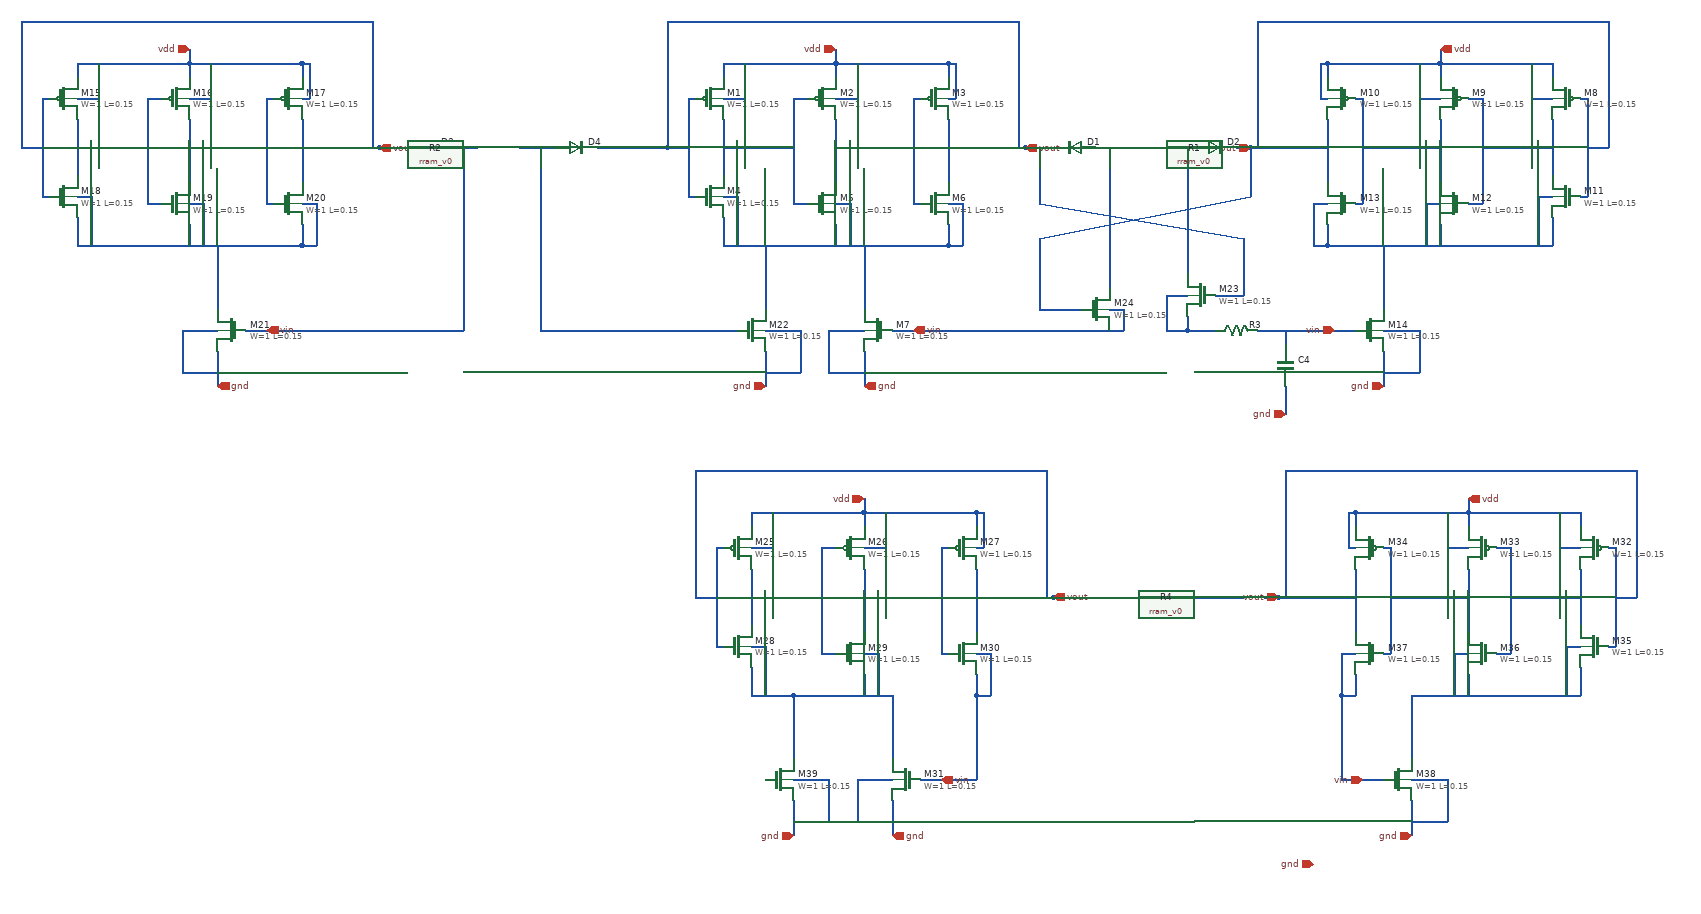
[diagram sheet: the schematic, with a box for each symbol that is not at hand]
v {xschem version=3.4.5 file_version=1.2
}
G {}
K {}
V {}
S {}
E {}
N 170 -200 170 -120 {
lab=#net1}
N 330 -200 330 -110 {
lab=#net2}
N 490 -200 490 -110 {
lab=vout}
N 270 -230 290 -230 {
lab=#net1}
N 270 -230 270 -80 {
lab=#net1}
N 270 -80 290 -80 {
lab=#net1}
N 440 -80 450 -80 {
lab=#net2}
N 440 -230 440 -80 {
lab=#net2}
N 440 -230 450 -230 {
lab=#net2}
N 120 -90 130 -90 {
lab=vout}
N 120 -230 120 -90 {
lab=vout}
N 120 -230 130 -230 {
lab=vout}
N 170 -280 170 -260 {
lab=vdd}
N 170 -280 330 -280 {
lab=vdd}
N 330 -300 330 -280 {
lab=vdd}
N 330 -280 490 -280 {
lab=vdd}
N 490 -280 490 -260 {
lab=vdd}
N 330 -280 330 -260 {
lab=vdd}
N 170 -160 270 -160 {
lab=#net1}
N 330 -160 440 -160 {
lab=#net2}
N 490 -160 520 -160 {
lab=vout}
N 520 -160 600 -160 {
lab=vout}
N 590 -160 600 -160 {
lab=vout}
N 590 -340 590 -160 {
lab=vout}
N 90 -340 590 -340 {
lab=vout}
N 90 -340 90 -160 {
lab=vout}
N 90 -160 120 -160 {
lab=vout}
N 170 -60 170 -20 {
lab=#net3}
N 170 -20 490 -20 {
lab=#net3}
N 490 -50 490 -20 {
lab=#net3}
N 330 -50 330 -20 {
lab=#net3}
N 370 -20 370 70 {
lab=#net3}
N 370 130 370 180 {
lab=gnd}
N 320 100 370 100 {
lab=gnd}
N 320 100 320 160 {
lab=gnd}
N 320 160 370 160 {
lab=gnd}
N 330 -80 350 -80 {
lab=#net3}
N 350 -80 350 -20 {
lab=#net3}
N 490 -80 510 -80 {
lab=#net3}
N 510 -80 510 -20 {
lab=#net3}
N 490 -20 510 -20 {
lab=#net3}
N 170 -90 190 -90 {
lab=#net3}
N 190 -90 190 -20 {
lab=#net3}
N 200 -280 200 -230 {
lab=vdd}
N 170 -230 200 -230 {
lab=vdd}
N 330 -230 360 -230 {
lab=vdd}
N 360 -280 360 -230 {
lab=vdd}
N 490 -230 500 -230 {
lab=vdd}
N 500 -280 500 -230 {
lab=vdd}
N 490 -280 500 -280 {
lab=vdd}
N 410 100 440 100 {
lab=vin}
N 1350 -200 1350 -120 {
lab=#net4}
N 1190 -200 1190 -110 {
lab=#net5}
N 1030 -200 1030 -110 {
lab=vout}
N 1230 -230 1250 -230 {
lab=#net4}
N 1250 -230 1250 -80 {
lab=#net4}
N 1230 -80 1250 -80 {
lab=#net4}
N 1070 -80 1080 -80 {
lab=#net5}
N 1080 -230 1080 -80 {
lab=#net5}
N 1070 -230 1080 -230 {
lab=#net5}
N 1390 -90 1400 -90 {
lab=vout}
N 1400 -230 1400 -90 {
lab=vout}
N 1390 -230 1400 -230 {
lab=vout}
N 1350 -280 1350 -260 {
lab=vdd}
N 1190 -280 1350 -280 {
lab=vdd}
N 1190 -300 1190 -280 {
lab=vdd}
N 1030 -280 1190 -280 {
lab=vdd}
N 1030 -280 1030 -260 {
lab=vdd}
N 1190 -280 1190 -260 {
lab=vdd}
N 1250 -160 1350 -160 {
lab=#net4}
N 1080 -160 1190 -160 {
lab=#net5}
N 1000 -160 1030 -160 {
lab=vout}
N 920 -160 1000 -160 {
lab=vout}
N 920 -160 930 -160 {
lab=vout}
N 930 -340 930 -160 {
lab=vout}
N 930 -340 1430 -340 {
lab=vout}
N 1430 -340 1430 -160 {
lab=vout}
N 1400 -160 1430 -160 {
lab=vout}
N 1350 -60 1350 -20 {
lab=#net6}
N 1030 -20 1350 -20 {
lab=#net6}
N 1030 -50 1030 -20 {
lab=#net6}
N 1190 -50 1190 -20 {
lab=#net6}
N 1110 -20 1110 70 {
lab=#net6}
N 1110 130 1110 180 {
lab=gnd}
N 1110 100 1160 100 {
lab=gnd}
N 1160 100 1160 160 {
lab=gnd}
N 1110 160 1160 160 {
lab=gnd}
N 1170 -80 1190 -80 {
lab=#net6}
N 1170 -80 1170 -20 {
lab=#net6}
N 1010 -80 1030 -80 {
lab=#net6}
N 1010 -80 1010 -20 {
lab=#net6}
N 1010 -20 1030 -20 {
lab=#net6}
N 1330 -90 1350 -90 {
lab=#net6}
N 1330 -90 1330 -20 {
lab=#net6}
N 1320 -280 1320 -230 {
lab=vdd}
N 1320 -230 1350 -230 {
lab=vdd}
N 1160 -230 1190 -230 {
lab=vdd}
N 1160 -280 1160 -230 {
lab=vdd}
N 1020 -230 1030 -230 {
lab=vdd}
N 1020 -280 1020 -230 {
lab=vdd}
N 1020 -280 1030 -280 {
lab=vdd}
N 1040 100 1070 100 {
lab=vin}
N 600 -160 640 -160 {
lab=vout}
N 700 -160 740 -160 {
lab=#net7}
N 900 -160 920 -160 {
lab=vout}
N 800 -160 840 -160 {
lab=#net8}
N 440 100 720 100 {
lab=vin}
N -750 -200 -750 -120 {
lab=#net9}
N -590 -200 -590 -110 {
lab=#net10}
N -430 -200 -430 -110 {
lab=vout}
N -650 -230 -630 -230 {
lab=#net9}
N -650 -230 -650 -80 {
lab=#net9}
N -650 -80 -630 -80 {
lab=#net9}
N -480 -80 -470 -80 {
lab=#net10}
N -480 -230 -480 -80 {
lab=#net10}
N -480 -230 -470 -230 {
lab=#net10}
N -800 -90 -790 -90 {
lab=vout}
N -800 -230 -800 -90 {
lab=vout}
N -800 -230 -790 -230 {
lab=vout}
N -750 -280 -750 -260 {
lab=vdd}
N -750 -280 -590 -280 {
lab=vdd}
N -590 -300 -590 -280 {
lab=vdd}
N -590 -280 -430 -280 {
lab=vdd}
N -430 -280 -430 -260 {
lab=vdd}
N -590 -280 -590 -260 {
lab=vdd}
N -750 -160 -650 -160 {
lab=#net9}
N -590 -160 -480 -160 {
lab=#net10}
N -430 -160 -400 -160 {
lab=vout}
N -400 -160 -320 -160 {
lab=vout}
N -330 -160 -320 -160 {
lab=vout}
N -330 -340 -330 -160 {
lab=vout}
N -830 -340 -330 -340 {
lab=vout}
N -830 -340 -830 -160 {
lab=vout}
N -830 -160 -800 -160 {
lab=vout}
N -750 -60 -750 -20 {
lab=#net11}
N -750 -20 -430 -20 {
lab=#net11}
N -430 -50 -430 -20 {
lab=#net11}
N -590 -50 -590 -20 {
lab=#net11}
N -550 -20 -550 70 {
lab=#net11}
N -550 130 -550 180 {
lab=gnd}
N -600 100 -550 100 {
lab=gnd}
N -600 100 -600 160 {
lab=gnd}
N -600 160 -550 160 {
lab=gnd}
N -590 -80 -570 -80 {
lab=#net11}
N -570 -80 -570 -20 {
lab=#net11}
N -430 -80 -410 -80 {
lab=#net11}
N -410 -80 -410 -20 {
lab=#net11}
N -430 -20 -410 -20 {
lab=#net11}
N -750 -90 -730 -90 {
lab=#net11}
N -730 -90 -730 -20 {
lab=#net11}
N -720 -280 -720 -230 {
lab=vdd}
N -750 -230 -720 -230 {
lab=vdd}
N -590 -230 -560 -230 {
lab=vdd}
N -560 -280 -560 -230 {
lab=vdd}
N -430 -230 -420 -230 {
lab=vdd}
N -420 -280 -420 -230 {
lab=vdd}
N -430 -280 -420 -280 {
lab=vdd}
N -510 100 -480 100 {
lab=vin}
N -320 -160 -280 -160 {
lab=vout}
N -220 -160 -180 -160 {
lab=vin}
N -200 -160 -200 100 {
lab=vin}
N -480 100 -200 100 {
lab=vin}
N -120 -160 -70 -160 {
lab=#net12}
N -10 -160 90 -160 {
lab=vout}
N -90 -160 -90 100 {
lab=#net12}
N 230 -20 230 70 {
lab=#net3}
N 230 130 230 180 {
lab=gnd}
N 230 100 280 100 {
lab=gnd}
N 280 100 280 160 {
lab=gnd}
N 230 160 280 160 {
lab=gnd}
N -90 100 190 100 {
lab=#net12}
N 830 100 870 100 {
lab=#net13}
N 970 100 970 120 {
lab=vin}
N 930 100 970 100 {
lab=vin}
N 930 100 1040 100 {
lab=vin}
N 970 180 970 220 {
lab=gnd}
N 830 80 830 100 {
lab=#net13}
N 830 -160 830 20 {
lab=#net8}
N 800 50 830 50 {
lab=#net13}
N 800 50 800 100 {
lab=#net13}
N 800 100 830 100 {
lab=#net13}
N 870 50 890 50 {
lab=vout}
N 720 70 740 70 {
lab=vin}
N 740 70 740 100 {
lab=vin}
N 720 100 740 100 {
lab=vin}
N 720 -160 720 40 {
lab=#net7}
N 650 70 680 70 {
lab=vout}
N 620 -160 620 -80 {
lab=vout}
N 620 -80 910 -30 {
lab=vout}
N 910 -30 910 50 {
lab=vout}
N 890 50 910 50 {
lab=vout}
N 920 -160 920 -90 {
lab=vout}
N 620 -30 920 -90 {
lab=vout}
N 620 -30 620 70 {
lab=vout}
N 620 70 650 70 {
lab=vout}
N 210 440 210 520 {
lab=#net14}
N 370 440 370 530 {
lab=#net15}
N 530 440 530 530 {
lab=vout}
N 310 410 330 410 {
lab=#net14}
N 310 410 310 560 {
lab=#net14}
N 310 560 330 560 {
lab=#net14}
N 480 560 490 560 {
lab=#net15}
N 480 410 480 560 {
lab=#net15}
N 480 410 490 410 {
lab=#net15}
N 160 550 170 550 {
lab=vout}
N 160 410 160 550 {
lab=vout}
N 160 410 170 410 {
lab=vout}
N 210 360 210 380 {
lab=vdd}
N 210 360 370 360 {
lab=vdd}
N 370 340 370 360 {
lab=vdd}
N 370 360 530 360 {
lab=vdd}
N 530 360 530 380 {
lab=vdd}
N 370 360 370 380 {
lab=vdd}
N 210 480 310 480 {
lab=#net14}
N 370 480 480 480 {
lab=#net15}
N 530 480 560 480 {
lab=vout}
N 560 480 640 480 {
lab=vout}
N 630 480 640 480 {
lab=vout}
N 630 300 630 480 {
lab=vout}
N 130 300 630 300 {
lab=vout}
N 130 300 130 480 {
lab=vout}
N 130 480 160 480 {
lab=vout}
N 210 580 210 620 {
lab=#net16}
N 530 590 530 620 {
lab=#net16}
N 370 590 370 620 {
lab=#net16}
N 410 620 410 710 {
lab=#net16}
N 410 770 410 820 {
lab=gnd}
N 360 740 410 740 {
lab=gnd}
N 360 740 360 800 {
lab=gnd}
N 360 800 410 800 {
lab=gnd}
N 370 560 390 560 {
lab=#net16}
N 390 560 390 620 {
lab=#net16}
N 530 560 550 560 {
lab=#net16}
N 550 560 550 620 {
lab=#net16}
N 530 620 550 620 {
lab=#net16}
N 210 550 230 550 {
lab=#net16}
N 230 550 230 620 {
lab=#net16}
N 240 360 240 410 {
lab=vdd}
N 210 410 240 410 {
lab=vdd}
N 370 410 400 410 {
lab=vdd}
N 400 360 400 410 {
lab=vdd}
N 530 410 540 410 {
lab=vdd}
N 540 360 540 410 {
lab=vdd}
N 530 360 540 360 {
lab=vdd}
N 450 740 480 740 {
lab=vin}
N 1390 440 1390 520 {
lab=#net17}
N 1230 440 1230 530 {
lab=#net18}
N 1070 440 1070 530 {
lab=vout}
N 1270 410 1290 410 {
lab=#net17}
N 1290 410 1290 560 {
lab=#net17}
N 1270 560 1290 560 {
lab=#net17}
N 1110 560 1120 560 {
lab=#net18}
N 1120 410 1120 560 {
lab=#net18}
N 1110 410 1120 410 {
lab=#net18}
N 1430 550 1440 550 {
lab=vout}
N 1440 410 1440 550 {
lab=vout}
N 1430 410 1440 410 {
lab=vout}
N 1390 360 1390 380 {
lab=vdd}
N 1230 360 1390 360 {
lab=vdd}
N 1230 340 1230 360 {
lab=vdd}
N 1070 360 1230 360 {
lab=vdd}
N 1070 360 1070 380 {
lab=vdd}
N 1230 360 1230 380 {
lab=vdd}
N 1290 480 1390 480 {
lab=#net17}
N 1120 480 1230 480 {
lab=#net18}
N 1040 480 1070 480 {
lab=vout}
N 960 480 1040 480 {
lab=vout}
N 960 480 970 480 {
lab=vout}
N 970 300 970 480 {
lab=vout}
N 970 300 1470 300 {
lab=vout}
N 1470 300 1470 480 {
lab=vout}
N 1440 480 1470 480 {
lab=vout}
N 1390 580 1390 620 {
lab=#net19}
N 1070 590 1070 620 {
lab=#net19}
N 1230 590 1230 620 {
lab=#net19}
N 1150 620 1150 710 {
lab=#net19}
N 1150 770 1150 820 {
lab=gnd}
N 1150 740 1200 740 {
lab=gnd}
N 1200 740 1200 800 {
lab=gnd}
N 1150 800 1200 800 {
lab=gnd}
N 1210 560 1230 560 {
lab=#net19}
N 1210 560 1210 620 {
lab=#net19}
N 1050 560 1070 560 {
lab=#net19}
N 1050 560 1050 620 {
lab=#net19}
N 1050 620 1070 620 {
lab=#net19}
N 1370 550 1390 550 {
lab=#net19}
N 1370 550 1370 620 {
lab=#net19}
N 1360 360 1360 410 {
lab=vdd}
N 1360 410 1390 410 {
lab=vdd}
N 1200 410 1230 410 {
lab=vdd}
N 1200 360 1200 410 {
lab=vdd}
N 1060 410 1070 410 {
lab=vdd}
N 1060 360 1060 410 {
lab=vdd}
N 1060 360 1070 360 {
lab=vdd}
N 1080 740 1110 740 {
lab=vin}
N 640 480 680 480 {
lab=vout}
N 740 480 780 480 {
lab=#net20}
N 940 480 960 480 {
lab=vout}
N 840 480 880 480 {
lab=#net21}
N 270 620 270 710 {
lab=#net16}
N 270 770 270 820 {
lab=gnd}
N 270 740 320 740 {
lab=gnd}
N 320 740 320 800 {
lab=gnd}
N 270 800 320 800 {
lab=gnd}
N 680 480 740 480 {}
N 880 480 910 480 {}
N 270 620 410 620 {}
N 210 620 270 620 {}
N 530 620 530 740 {}
N 1150 620 1390 620 {}
N 1050 620 1050 740 {}
N 1050 740 1080 740 {}
N 480 740 530 740 {}
C {sky130_fd_pr/pfet_01v8.sym} 150 -230 0 0 {name=M1
L=0.15
W=1
nf=1
mult=1
ad="'int((nf+1)/2) * W/nf * 0.29'" 
pd="'2*int((nf+1)/2) * (W/nf + 0.29)'"
as="'int((nf+2)/2) * W/nf * 0.29'" 
ps="'2*int((nf+2)/2) * (W/nf + 0.29)'"
nrd="'0.29 / W'" nrs="'0.29 / W'"
sa=0 sb=0 sd=0
model=pfet_01v8
spiceprefix=X
}
C {sky130_fd_pr/pfet_01v8.sym} 310 -230 0 0 {name=M2
L=0.15
W=1
nf=1
mult=1
ad="'int((nf+1)/2) * W/nf * 0.29'" 
pd="'2*int((nf+1)/2) * (W/nf + 0.29)'"
as="'int((nf+2)/2) * W/nf * 0.29'" 
ps="'2*int((nf+2)/2) * (W/nf + 0.29)'"
nrd="'0.29 / W'" nrs="'0.29 / W'"
sa=0 sb=0 sd=0
model=pfet_01v8
spiceprefix=X
}
C {sky130_fd_pr/pfet_01v8.sym} 470 -230 0 0 {name=M3
L=0.15
W=1
nf=1
mult=1
ad="'int((nf+1)/2) * W/nf * 0.29'" 
pd="'2*int((nf+1)/2) * (W/nf + 0.29)'"
as="'int((nf+2)/2) * W/nf * 0.29'" 
ps="'2*int((nf+2)/2) * (W/nf + 0.29)'"
nrd="'0.29 / W'" nrs="'0.29 / W'"
sa=0 sb=0 sd=0
model=pfet_01v8
spiceprefix=X
}
C {sky130_fd_pr/nfet_01v8.sym} 150 -90 0 0 {name=M4
L=0.15
W=1
nf=1 
mult=1
ad="'int((nf+1)/2) * W/nf * 0.29'" 
pd="'2*int((nf+1)/2) * (W/nf + 0.29)'"
as="'int((nf+2)/2) * W/nf * 0.29'" 
ps="'2*int((nf+2)/2) * (W/nf + 0.29)'"
nrd="'0.29 / W'" nrs="'0.29 / W'"
sa=0 sb=0 sd=0
model=nfet_01v8
spiceprefix=X
}
C {sky130_fd_pr/nfet_01v8.sym} 310 -80 0 0 {name=M5
L=0.15
W=1
nf=1 
mult=1
ad="'int((nf+1)/2) * W/nf * 0.29'" 
pd="'2*int((nf+1)/2) * (W/nf + 0.29)'"
as="'int((nf+2)/2) * W/nf * 0.29'" 
ps="'2*int((nf+2)/2) * (W/nf + 0.29)'"
nrd="'0.29 / W'" nrs="'0.29 / W'"
sa=0 sb=0 sd=0
model=nfet_01v8
spiceprefix=X
}
C {sky130_fd_pr/nfet_01v8.sym} 470 -80 0 0 {name=M6
L=0.15
W=1
nf=1 
mult=1
ad="'int((nf+1)/2) * W/nf * 0.29'" 
pd="'2*int((nf+1)/2) * (W/nf + 0.29)'"
as="'int((nf+2)/2) * W/nf * 0.29'" 
ps="'2*int((nf+2)/2) * (W/nf + 0.29)'"
nrd="'0.29 / W'" nrs="'0.29 / W'"
sa=0 sb=0 sd=0
model=nfet_01v8
spiceprefix=X
}
C {sky130_fd_pr/nfet_01v8.sym} 390 100 0 1 {name=M7
L=0.15
W=1
nf=1 
mult=1
ad="'int((nf+1)/2) * W/nf * 0.29'" 
pd="'2*int((nf+1)/2) * (W/nf + 0.29)'"
as="'int((nf+2)/2) * W/nf * 0.29'" 
ps="'2*int((nf+2)/2) * (W/nf + 0.29)'"
nrd="'0.29 / W'" nrs="'0.29 / W'"
sa=0 sb=0 sd=0
model=nfet_01v8
spiceprefix=X
}
C {devices/iopin.sym} 370 180 3 1 {name=p1 lab=gnd}
C {devices/iopin.sym} 330 -300 2 0 {name=p2 lab=vdd}
C {devices/ipin.sym} 440 100 0 1 {name=p3 lab=vin}
C {devices/opin.sym} 600 -160 0 0 {name=p4 lab=vout}
C {sky130_fd_pr/pfet_01v8.sym} 1370 -230 0 1 {name=M8
L=0.15
W=1
nf=1
mult=1
ad="'int((nf+1)/2) * W/nf * 0.29'" 
pd="'2*int((nf+1)/2) * (W/nf + 0.29)'"
as="'int((nf+2)/2) * W/nf * 0.29'" 
ps="'2*int((nf+2)/2) * (W/nf + 0.29)'"
nrd="'0.29 / W'" nrs="'0.29 / W'"
sa=0 sb=0 sd=0
model=pfet_01v8
spiceprefix=X
}
C {sky130_fd_pr/pfet_01v8.sym} 1210 -230 0 1 {name=M9
L=0.15
W=1
nf=1
mult=1
ad="'int((nf+1)/2) * W/nf * 0.29'" 
pd="'2*int((nf+1)/2) * (W/nf + 0.29)'"
as="'int((nf+2)/2) * W/nf * 0.29'" 
ps="'2*int((nf+2)/2) * (W/nf + 0.29)'"
nrd="'0.29 / W'" nrs="'0.29 / W'"
sa=0 sb=0 sd=0
model=pfet_01v8
spiceprefix=X
}
C {sky130_fd_pr/pfet_01v8.sym} 1050 -230 0 1 {name=M10
L=0.15
W=1
nf=1
mult=1
ad="'int((nf+1)/2) * W/nf * 0.29'" 
pd="'2*int((nf+1)/2) * (W/nf + 0.29)'"
as="'int((nf+2)/2) * W/nf * 0.29'" 
ps="'2*int((nf+2)/2) * (W/nf + 0.29)'"
nrd="'0.29 / W'" nrs="'0.29 / W'"
sa=0 sb=0 sd=0
model=pfet_01v8
spiceprefix=X
}
C {sky130_fd_pr/nfet_01v8.sym} 1370 -90 0 1 {name=M11
L=0.15
W=1
nf=1 
mult=1
ad="'int((nf+1)/2) * W/nf * 0.29'" 
pd="'2*int((nf+1)/2) * (W/nf + 0.29)'"
as="'int((nf+2)/2) * W/nf * 0.29'" 
ps="'2*int((nf+2)/2) * (W/nf + 0.29)'"
nrd="'0.29 / W'" nrs="'0.29 / W'"
sa=0 sb=0 sd=0
model=nfet_01v8
spiceprefix=X
}
C {sky130_fd_pr/nfet_01v8.sym} 1210 -80 0 1 {name=M12
L=0.15
W=1
nf=1 
mult=1
ad="'int((nf+1)/2) * W/nf * 0.29'" 
pd="'2*int((nf+1)/2) * (W/nf + 0.29)'"
as="'int((nf+2)/2) * W/nf * 0.29'" 
ps="'2*int((nf+2)/2) * (W/nf + 0.29)'"
nrd="'0.29 / W'" nrs="'0.29 / W'"
sa=0 sb=0 sd=0
model=nfet_01v8
spiceprefix=X
}
C {sky130_fd_pr/nfet_01v8.sym} 1050 -80 0 1 {name=M13
L=0.15
W=1
nf=1 
mult=1
ad="'int((nf+1)/2) * W/nf * 0.29'" 
pd="'2*int((nf+1)/2) * (W/nf + 0.29)'"
as="'int((nf+2)/2) * W/nf * 0.29'" 
ps="'2*int((nf+2)/2) * (W/nf + 0.29)'"
nrd="'0.29 / W'" nrs="'0.29 / W'"
sa=0 sb=0 sd=0
model=nfet_01v8
spiceprefix=X
}
C {sky130_fd_pr/nfet_01v8.sym} 1090 100 0 0 {name=M14
L=0.15
W=1
nf=1 
mult=1
ad="'int((nf+1)/2) * W/nf * 0.29'" 
pd="'2*int((nf+1)/2) * (W/nf + 0.29)'"
as="'int((nf+2)/2) * W/nf * 0.29'" 
ps="'2*int((nf+2)/2) * (W/nf + 0.29)'"
nrd="'0.29 / W'" nrs="'0.29 / W'"
sa=0 sb=0 sd=0
model=nfet_01v8
spiceprefix=X
}
C {devices/iopin.sym} 1110 180 1 0 {name=p5 lab=gnd}
C {devices/iopin.sym} 1190 -300 2 1 {name=p6 lab=vdd}
C {devices/ipin.sym} 1040 100 0 0 {name=p7 lab=vin}
C {devices/opin.sym} 920 -160 0 1 {name=p8 lab=vout}
C {sky130_fd_pr/rram_v0.sym} 770 -160 3 0 {name=R1}
C {sky130_fd_pr/diode.sym} 670 -160 1 0 {name=D1}
C {sky130_fd_pr/diode.sym} 870 -160 3 0 {name=D2}
C {sky130_fd_pr/pfet_01v8.sym} -770 -230 0 0 {name=M15
L=0.15
W=1
nf=1
mult=1
ad="'int((nf+1)/2) * W/nf * 0.29'" 
pd="'2*int((nf+1)/2) * (W/nf + 0.29)'"
as="'int((nf+2)/2) * W/nf * 0.29'" 
ps="'2*int((nf+2)/2) * (W/nf + 0.29)'"
nrd="'0.29 / W'" nrs="'0.29 / W'"
sa=0 sb=0 sd=0
model=pfet_01v8
spiceprefix=X
}
C {sky130_fd_pr/pfet_01v8.sym} -610 -230 0 0 {name=M16
L=0.15
W=1
nf=1
mult=1
ad="'int((nf+1)/2) * W/nf * 0.29'" 
pd="'2*int((nf+1)/2) * (W/nf + 0.29)'"
as="'int((nf+2)/2) * W/nf * 0.29'" 
ps="'2*int((nf+2)/2) * (W/nf + 0.29)'"
nrd="'0.29 / W'" nrs="'0.29 / W'"
sa=0 sb=0 sd=0
model=pfet_01v8
spiceprefix=X
}
C {sky130_fd_pr/pfet_01v8.sym} -450 -230 0 0 {name=M17
L=0.15
W=1
nf=1
mult=1
ad="'int((nf+1)/2) * W/nf * 0.29'" 
pd="'2*int((nf+1)/2) * (W/nf + 0.29)'"
as="'int((nf+2)/2) * W/nf * 0.29'" 
ps="'2*int((nf+2)/2) * (W/nf + 0.29)'"
nrd="'0.29 / W'" nrs="'0.29 / W'"
sa=0 sb=0 sd=0
model=pfet_01v8
spiceprefix=X
}
C {sky130_fd_pr/nfet_01v8.sym} -770 -90 0 0 {name=M18
L=0.15
W=1
nf=1 
mult=1
ad="'int((nf+1)/2) * W/nf * 0.29'" 
pd="'2*int((nf+1)/2) * (W/nf + 0.29)'"
as="'int((nf+2)/2) * W/nf * 0.29'" 
ps="'2*int((nf+2)/2) * (W/nf + 0.29)'"
nrd="'0.29 / W'" nrs="'0.29 / W'"
sa=0 sb=0 sd=0
model=nfet_01v8
spiceprefix=X
}
C {sky130_fd_pr/nfet_01v8.sym} -610 -80 0 0 {name=M19
L=0.15
W=1
nf=1 
mult=1
ad="'int((nf+1)/2) * W/nf * 0.29'" 
pd="'2*int((nf+1)/2) * (W/nf + 0.29)'"
as="'int((nf+2)/2) * W/nf * 0.29'" 
ps="'2*int((nf+2)/2) * (W/nf + 0.29)'"
nrd="'0.29 / W'" nrs="'0.29 / W'"
sa=0 sb=0 sd=0
model=nfet_01v8
spiceprefix=X
}
C {sky130_fd_pr/nfet_01v8.sym} -450 -80 0 0 {name=M20
L=0.15
W=1
nf=1 
mult=1
ad="'int((nf+1)/2) * W/nf * 0.29'" 
pd="'2*int((nf+1)/2) * (W/nf + 0.29)'"
as="'int((nf+2)/2) * W/nf * 0.29'" 
ps="'2*int((nf+2)/2) * (W/nf + 0.29)'"
nrd="'0.29 / W'" nrs="'0.29 / W'"
sa=0 sb=0 sd=0
model=nfet_01v8
spiceprefix=X
}
C {sky130_fd_pr/nfet_01v8.sym} -530 100 0 1 {name=M21
L=0.15
W=1
nf=1 
mult=1
ad="'int((nf+1)/2) * W/nf * 0.29'" 
pd="'2*int((nf+1)/2) * (W/nf + 0.29)'"
as="'int((nf+2)/2) * W/nf * 0.29'" 
ps="'2*int((nf+2)/2) * (W/nf + 0.29)'"
nrd="'0.29 / W'" nrs="'0.29 / W'"
sa=0 sb=0 sd=0
model=nfet_01v8
spiceprefix=X
}
C {devices/iopin.sym} -550 180 3 1 {name=p9 lab=gnd}
C {devices/iopin.sym} -590 -300 2 0 {name=p10 lab=vdd}
C {devices/ipin.sym} -480 100 0 1 {name=p11 lab=vin}
C {devices/opin.sym} -320 -160 0 0 {name=p12 lab=vout}
C {sky130_fd_pr/diode.sym} -250 -160 1 0 {name=D3}
C {sky130_fd_pr/rram_v0.sym} -150 -160 3 0 {name=R2}
C {sky130_fd_pr/diode.sym} -40 -160 3 0 {name=D4}
C {sky130_fd_pr/nfet_01v8.sym} 210 100 0 0 {name=M22
L=0.15
W=1
nf=1 
mult=1
ad="'int((nf+1)/2) * W/nf * 0.29'" 
pd="'2*int((nf+1)/2) * (W/nf + 0.29)'"
as="'int((nf+2)/2) * W/nf * 0.29'" 
ps="'2*int((nf+2)/2) * (W/nf + 0.29)'"
nrd="'0.29 / W'" nrs="'0.29 / W'"
sa=0 sb=0 sd=0
model=nfet_01v8
spiceprefix=X
}
C {devices/iopin.sym} 230 180 1 0 {name=p13 lab=gnd}
C {devices/res.sym} 900 100 3 0 {name=R3}
C {devices/capa.sym} 970 150 0 0 {name=C4}
C {devices/iopin.sym} 970 220 1 0 {name=p14 lab=gnd}
C {sky130_fd_pr/nfet_01v8.sym} 850 50 0 1 {name=M23
L=0.15
W=1
nf=1 
mult=1
ad="'int((nf+1)/2) * W/nf * 0.29'" 
pd="'2*int((nf+1)/2) * (W/nf + 0.29)'"
as="'int((nf+2)/2) * W/nf * 0.29'" 
ps="'2*int((nf+2)/2) * (W/nf + 0.29)'"
nrd="'0.29 / W'" nrs="'0.29 / W'"
sa=0 sb=0 sd=0
model=nfet_01v8
spiceprefix=X
}
C {sky130_fd_pr/nfet_01v8.sym} 700 70 0 0 {name=M24
L=0.15
W=1
nf=1 
mult=1
ad="'int((nf+1)/2) * W/nf * 0.29'" 
pd="'2*int((nf+1)/2) * (W/nf + 0.29)'"
as="'int((nf+2)/2) * W/nf * 0.29'" 
ps="'2*int((nf+2)/2) * (W/nf + 0.29)'"
nrd="'0.29 / W'" nrs="'0.29 / W'"
sa=0 sb=0 sd=0
model=nfet_01v8
spiceprefix=X
}
C {sky130_fd_pr/pfet_01v8.sym} 190 410 0 0 {name=M25
L=0.15
W=1
nf=1
mult=1
ad="'int((nf+1)/2) * W/nf * 0.29'" 
pd="'2*int((nf+1)/2) * (W/nf + 0.29)'"
as="'int((nf+2)/2) * W/nf * 0.29'" 
ps="'2*int((nf+2)/2) * (W/nf + 0.29)'"
nrd="'0.29 / W'" nrs="'0.29 / W'"
sa=0 sb=0 sd=0
model=pfet_01v8
spiceprefix=X
}
C {sky130_fd_pr/pfet_01v8.sym} 350 410 0 0 {name=M26
L=0.15
W=1
nf=1
mult=1
ad="'int((nf+1)/2) * W/nf * 0.29'" 
pd="'2*int((nf+1)/2) * (W/nf + 0.29)'"
as="'int((nf+2)/2) * W/nf * 0.29'" 
ps="'2*int((nf+2)/2) * (W/nf + 0.29)'"
nrd="'0.29 / W'" nrs="'0.29 / W'"
sa=0 sb=0 sd=0
model=pfet_01v8
spiceprefix=X
}
C {sky130_fd_pr/pfet_01v8.sym} 510 410 0 0 {name=M27
L=0.15
W=1
nf=1
mult=1
ad="'int((nf+1)/2) * W/nf * 0.29'" 
pd="'2*int((nf+1)/2) * (W/nf + 0.29)'"
as="'int((nf+2)/2) * W/nf * 0.29'" 
ps="'2*int((nf+2)/2) * (W/nf + 0.29)'"
nrd="'0.29 / W'" nrs="'0.29 / W'"
sa=0 sb=0 sd=0
model=pfet_01v8
spiceprefix=X
}
C {sky130_fd_pr/nfet_01v8.sym} 190 550 0 0 {name=M28
L=0.15
W=1
nf=1 
mult=1
ad="'int((nf+1)/2) * W/nf * 0.29'" 
pd="'2*int((nf+1)/2) * (W/nf + 0.29)'"
as="'int((nf+2)/2) * W/nf * 0.29'" 
ps="'2*int((nf+2)/2) * (W/nf + 0.29)'"
nrd="'0.29 / W'" nrs="'0.29 / W'"
sa=0 sb=0 sd=0
model=nfet_01v8
spiceprefix=X
}
C {sky130_fd_pr/nfet_01v8.sym} 350 560 0 0 {name=M29
L=0.15
W=1
nf=1 
mult=1
ad="'int((nf+1)/2) * W/nf * 0.29'" 
pd="'2*int((nf+1)/2) * (W/nf + 0.29)'"
as="'int((nf+2)/2) * W/nf * 0.29'" 
ps="'2*int((nf+2)/2) * (W/nf + 0.29)'"
nrd="'0.29 / W'" nrs="'0.29 / W'"
sa=0 sb=0 sd=0
model=nfet_01v8
spiceprefix=X
}
C {sky130_fd_pr/nfet_01v8.sym} 510 560 0 0 {name=M30
L=0.15
W=1
nf=1 
mult=1
ad="'int((nf+1)/2) * W/nf * 0.29'" 
pd="'2*int((nf+1)/2) * (W/nf + 0.29)'"
as="'int((nf+2)/2) * W/nf * 0.29'" 
ps="'2*int((nf+2)/2) * (W/nf + 0.29)'"
nrd="'0.29 / W'" nrs="'0.29 / W'"
sa=0 sb=0 sd=0
model=nfet_01v8
spiceprefix=X
}
C {sky130_fd_pr/nfet_01v8.sym} 430 740 0 1 {name=M31
L=0.15
W=1
nf=1 
mult=1
ad="'int((nf+1)/2) * W/nf * 0.29'" 
pd="'2*int((nf+1)/2) * (W/nf + 0.29)'"
as="'int((nf+2)/2) * W/nf * 0.29'" 
ps="'2*int((nf+2)/2) * (W/nf + 0.29)'"
nrd="'0.29 / W'" nrs="'0.29 / W'"
sa=0 sb=0 sd=0
model=nfet_01v8
spiceprefix=X
}
C {devices/iopin.sym} 410 820 3 1 {name=p15 lab=gnd}
C {devices/iopin.sym} 370 340 2 0 {name=p16 lab=vdd}
C {devices/ipin.sym} 480 740 0 1 {name=p17 lab=vin}
C {devices/opin.sym} 640 480 0 0 {name=p18 lab=vout}
C {sky130_fd_pr/pfet_01v8.sym} 1410 410 0 1 {name=M32
L=0.15
W=1
nf=1
mult=1
ad="'int((nf+1)/2) * W/nf * 0.29'" 
pd="'2*int((nf+1)/2) * (W/nf + 0.29)'"
as="'int((nf+2)/2) * W/nf * 0.29'" 
ps="'2*int((nf+2)/2) * (W/nf + 0.29)'"
nrd="'0.29 / W'" nrs="'0.29 / W'"
sa=0 sb=0 sd=0
model=pfet_01v8
spiceprefix=X
}
C {sky130_fd_pr/pfet_01v8.sym} 1250 410 0 1 {name=M33
L=0.15
W=1
nf=1
mult=1
ad="'int((nf+1)/2) * W/nf * 0.29'" 
pd="'2*int((nf+1)/2) * (W/nf + 0.29)'"
as="'int((nf+2)/2) * W/nf * 0.29'" 
ps="'2*int((nf+2)/2) * (W/nf + 0.29)'"
nrd="'0.29 / W'" nrs="'0.29 / W'"
sa=0 sb=0 sd=0
model=pfet_01v8
spiceprefix=X
}
C {sky130_fd_pr/pfet_01v8.sym} 1090 410 0 1 {name=M34
L=0.15
W=1
nf=1
mult=1
ad="'int((nf+1)/2) * W/nf * 0.29'" 
pd="'2*int((nf+1)/2) * (W/nf + 0.29)'"
as="'int((nf+2)/2) * W/nf * 0.29'" 
ps="'2*int((nf+2)/2) * (W/nf + 0.29)'"
nrd="'0.29 / W'" nrs="'0.29 / W'"
sa=0 sb=0 sd=0
model=pfet_01v8
spiceprefix=X
}
C {sky130_fd_pr/nfet_01v8.sym} 1410 550 0 1 {name=M35
L=0.15
W=1
nf=1 
mult=1
ad="'int((nf+1)/2) * W/nf * 0.29'" 
pd="'2*int((nf+1)/2) * (W/nf + 0.29)'"
as="'int((nf+2)/2) * W/nf * 0.29'" 
ps="'2*int((nf+2)/2) * (W/nf + 0.29)'"
nrd="'0.29 / W'" nrs="'0.29 / W'"
sa=0 sb=0 sd=0
model=nfet_01v8
spiceprefix=X
}
C {sky130_fd_pr/nfet_01v8.sym} 1250 560 0 1 {name=M36
L=0.15
W=1
nf=1 
mult=1
ad="'int((nf+1)/2) * W/nf * 0.29'" 
pd="'2*int((nf+1)/2) * (W/nf + 0.29)'"
as="'int((nf+2)/2) * W/nf * 0.29'" 
ps="'2*int((nf+2)/2) * (W/nf + 0.29)'"
nrd="'0.29 / W'" nrs="'0.29 / W'"
sa=0 sb=0 sd=0
model=nfet_01v8
spiceprefix=X
}
C {sky130_fd_pr/nfet_01v8.sym} 1090 560 0 1 {name=M37
L=0.15
W=1
nf=1 
mult=1
ad="'int((nf+1)/2) * W/nf * 0.29'" 
pd="'2*int((nf+1)/2) * (W/nf + 0.29)'"
as="'int((nf+2)/2) * W/nf * 0.29'" 
ps="'2*int((nf+2)/2) * (W/nf + 0.29)'"
nrd="'0.29 / W'" nrs="'0.29 / W'"
sa=0 sb=0 sd=0
model=nfet_01v8
spiceprefix=X
}
C {sky130_fd_pr/nfet_01v8.sym} 1130 740 0 0 {name=M38
L=0.15
W=1
nf=1 
mult=1
ad="'int((nf+1)/2) * W/nf * 0.29'" 
pd="'2*int((nf+1)/2) * (W/nf + 0.29)'"
as="'int((nf+2)/2) * W/nf * 0.29'" 
ps="'2*int((nf+2)/2) * (W/nf + 0.29)'"
nrd="'0.29 / W'" nrs="'0.29 / W'"
sa=0 sb=0 sd=0
model=nfet_01v8
spiceprefix=X
}
C {devices/iopin.sym} 1150 820 1 0 {name=p19 lab=gnd}
C {devices/iopin.sym} 1230 340 2 1 {name=p20 lab=vdd}
C {devices/ipin.sym} 1080 740 0 0 {name=p21 lab=vin}
C {devices/opin.sym} 960 480 0 1 {name=p22 lab=vout}
C {sky130_fd_pr/rram_v0.sym} 810 480 3 0 {name=R4}
C {sky130_fd_pr/nfet_01v8.sym} 250 740 0 0 {name=M39
L=0.15
W=1
nf=1 
mult=1
ad="'int((nf+1)/2) * W/nf * 0.29'" 
pd="'2*int((nf+1)/2) * (W/nf + 0.29)'"
as="'int((nf+2)/2) * W/nf * 0.29'" 
ps="'2*int((nf+2)/2) * (W/nf + 0.29)'"
nrd="'0.29 / W'" nrs="'0.29 / W'"
sa=0 sb=0 sd=0
model=nfet_01v8
spiceprefix=X
}
C {devices/iopin.sym} 270 820 1 0 {name=p23 lab=gnd}
C {devices/iopin.sym} 1010 860 1 0 {name=p24 lab=gnd}
